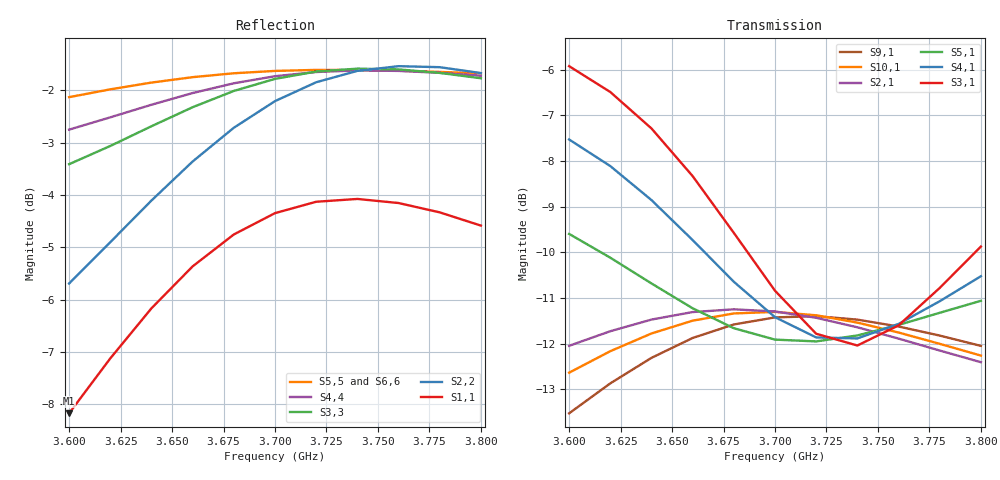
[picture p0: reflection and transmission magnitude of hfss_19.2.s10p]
! Touchstone file exported from HFSS 2019.3.0
!  File:  C:/Users/JH218595/Documents/Ansoft/test_10ports.aedt
!  Generated:  7:47:26  déc. 05, 2019
!  Design:  HFSSDesign1
!  Project:  test_10ports
!  Setup:  Setup1
!  Solution:  Sweep
!Data is not renormalized
# GHZ S MA
! Modal data exported
! Port[1] = 1:1
! Port[2] = 2:1
! Port[3] = 3:1
! Port[4] = 4:1
! Port[5] = 5:1
! Port[6] = 6:1
! Port[7] = 7:1
! Port[8] = 8:1
! Port[9] = 9:1
! Port[10] = 10:1
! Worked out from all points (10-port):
!   11 points, 3.6 GHz to 3.8 GHz, reference per port
!   strongest paths, dB at 3.6 GHz, 3.64 GHz, 3.7 GHz, 3.76 GHz, 3.8 GHz:
!     S3,1: -5.9, -7.3, -10.8, -11.6, -9.9
!     S4,1: -7.5, -8.9, -11.4, -11.6, -10.5
!     S5,1: -9.6, -10.7, -11.9, -11.6, -11.1
!     S2,1: -12.0, -11.5, -11.3, -11.9, -12.4
!     S10,1: -12.6, -11.8, -11.3, -11.8, -12.3
!     S9,1: -13.5, -12.3, -11.4, -11.6, -12.1
!   lowest |S11| = -8.2 dB at 3.6 GHz (marker M1), VSWR 2.28
!   |S11| at or under -10 dB: nowhere
